VERSION 5.6 ;
BUSBITCHARS "[]" ;
DIVIDERCHAR "/" ;

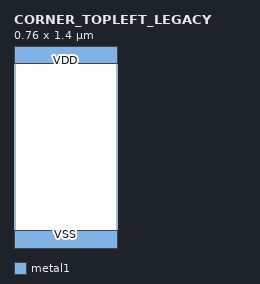
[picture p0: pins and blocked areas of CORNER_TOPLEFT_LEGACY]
MACRO CORNER_TOPLEFT_LEGACY
  CLASS ENDCAP TOPLEFT ;
  ORIGIN 0 0 ;
  FOREIGN CORNER_TOPLEFT_LEGACY 0 0 ;
  SIZE 0.76 BY 1.4 ;
  SYMMETRY X Y ;
  SITE FreePDK45_38x28_10R_NP_162NW_34O ;
  PIN VDD
    DIRECTION INOUT ;
    USE POWER ;
    SHAPE ABUTMENT ;
    PORT
      LAYER metal1 ;
        RECT 0 1.315 0.76 1.485 ;
    END
  END VDD
  PIN VSS
    DIRECTION INOUT ;
    USE GROUND ;
    SHAPE ABUTMENT ;
    PORT
      LAYER metal1 ;
        RECT 0 -0.085 0.76 0.085 ;
    END
  END VSS
END CORNER_TOPLEFT_LEGACY

END LIBRARY
